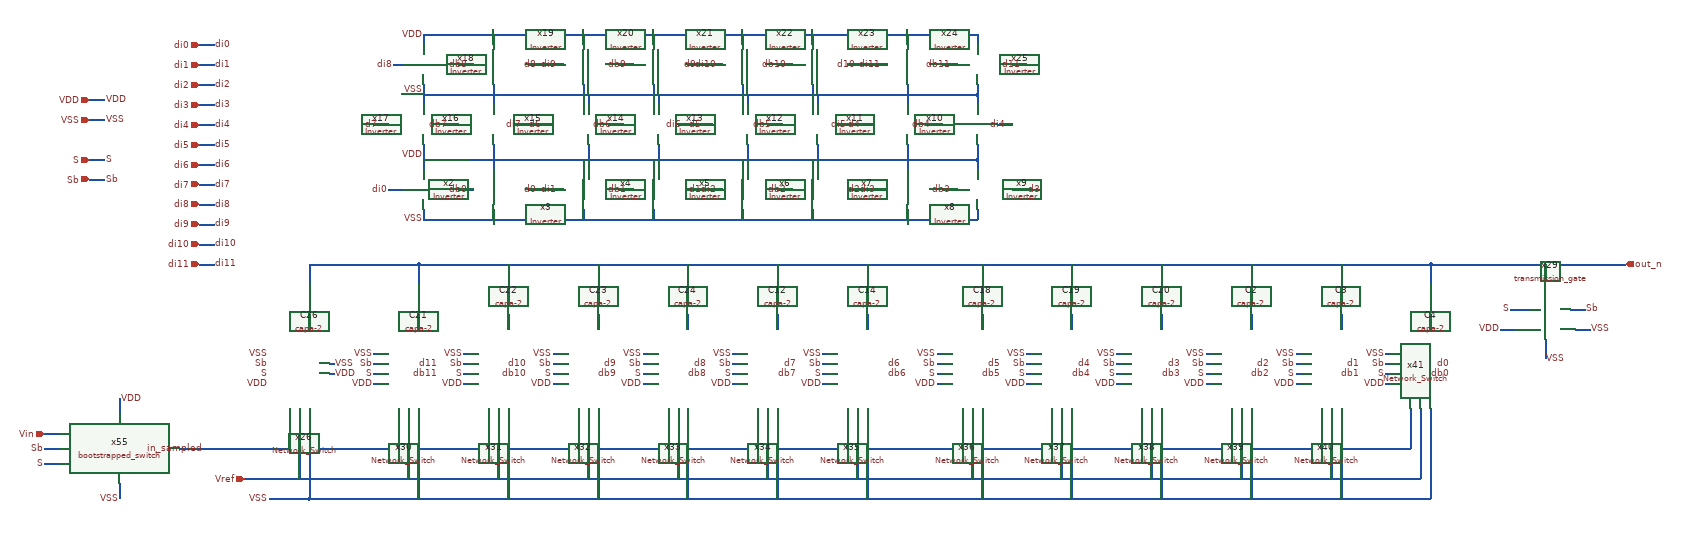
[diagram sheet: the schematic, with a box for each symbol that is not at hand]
v {xschem version=3.4.6 file_version=1.2}
G {}
K {}
V {}
S {}
E {}
N -780 60 -780 90 {lab=out_n}
N -520 60 200 60 {lab=out_n}
N 280 60 1000 60 {lab=out_n}
N 1250 60 1250 90 {lab=out_n}
N 1070 60 1070 90 {lab=out_n}
N 890 60 890 90 {lab=out_n}
N 710 60 710 90 {lab=out_n}
N 530 60 530 90 {lab=out_n}
N 350 60 350 90 {lab=out_n}
N 120 60 120 90 {lab=out_n}
N -60 60 -60 90 {lab=out_n}
N -240 60 -240 90 {lab=out_n}
N -420 60 -420 90 {lab=out_n}
N -600 60 -600 90 {lab=out_n}
N 1250 60 1640 60 {lab=out_n}
N -650 60 -520 60 {lab=out_n}
N -780 60 -650 60 {lab=out_n}
N -780 170 -780 190 {lab=#net1}
N -600 170 -600 190 {lab=#net2}
N -920 430 1210 430 {lab=in_p_sampled}
N 1210 350 1210 430 {lab=in_p_sampled}
N 1030 350 1030 430 {lab=in_p_sampled}
N 850 350 850 430 {lab=in_p_sampled}
N 670 350 670 430 {lab=in_p_sampled}
N 490 350 490 430 {lab=in_p_sampled}
N 310 350 310 430 {lab=in_p_sampled}
N -1440 -230 -1410 -230 {lab=VSS}
N -1440 -270 -1410 -270 {lab=VDD}
N -1440 -150 -1410 -150 {lab=S}
N -1440 -110 -1410 -110 {lab=Sb}
N -1220 -260 -1190 -260 {lab=di3}
N -1380 330 -1380 360 {lab=VDD}
N -870 300 -860 300 {lab=VDD}
N -690 300 -680 300 {lab=VDD}
N -510 300 -500 300 {lab=VDD}
N -330 300 -320 300 {lab=VDD}
N -150 300 -140 300 {lab=VDD}
N 30 300 40 300 {lab=VDD}
N 260 300 270 300 {lab=VDD}
N 440 300 450 300 {lab=VDD}
N 620 300 630 300 {lab=VDD}
N 980 300 990 300 {lab=VDD}
N 800 300 810 300 {lab=VDD}
N 1160 300 1170 300 {lab=VDD}
N -1380 500 -1380 530 {lab=VSS}
N -870 240 -860 240 {lab=VSS}
N -690 240 -680 240 {lab=VSS}
N -510 240 -500 240 {lab=VSS}
N -330 240 -320 240 {lab=VSS}
N -150 240 -140 240 {lab=VSS}
N 30 240 40 240 {lab=VSS}
N 260 240 270 240 {lab=VSS}
N 440 240 450 240 {lab=VSS}
N 620 240 630 240 {lab=VSS}
N 800 240 810 240 {lab=VSS}
N 980 240 990 240 {lab=VSS}
N 1160 240 1170 240 {lab=VSS}
N 1230 350 1230 490 {lab=Vref_p}
N -900 490 1230 490 {lab=Vref_p}
N 1250 350 1250 530 {lab=Vref_n}
N -920 530 1250 530 {lab=Vref_n}
N -800 350 -800 490 {lab=Vref_p}
N -780 350 -780 530 {lab=Vref_n}
N -620 350 -620 490 {lab=Vref_p}
N -600 350 -600 530 {lab=Vref_n}
N -440 350 -440 490 {lab=Vref_p}
N -420 350 -420 530 {lab=Vref_n}
N -260 350 -260 490 {lab=Vref_p}
N -240 350 -240 530 {lab=Vref_n}
N -80 350 -80 490 {lab=Vref_p}
N -60 350 -60 530 {lab=Vref_n}
N 100 350 100 490 {lab=Vref_p}
N 120 350 120 530 {lab=Vref_n}
N 330 350 330 490 {lab=Vref_p}
N 350 350 350 530 {lab=Vref_n}
N 510 350 510 490 {lab=Vref_p}
N 530 350 530 530 {lab=Vref_n}
N 690 350 690 490 {lab=Vref_p}
N 710 350 710 530 {lab=Vref_n}
N 870 350 870 490 {lab=Vref_p}
N 890 350 890 530 {lab=Vref_n}
N 1050 350 1050 490 {lab=Vref_p}
N 1070 350 1070 530 {lab=Vref_n}
N -1220 -380 -1190 -380 {lab=di0}
N -1220 -340 -1190 -340 {lab=di1}
N -1220 -300 -1190 -300 {lab=di2}
N -1220 -180 -1190 -180 {lab=di5}
N -1220 -220 -1190 -220 {lab=di4}
N -1220 -100 -1190 -100 {lab=di7}
N -1220 -140 -1190 -140 {lab=di6}
N -1220 -20 -1190 -20 {lab=di9}
N -1220 -60 -1190 -60 {lab=di8}
N -1220 60 -1190 60 {lab=di11}
N -1220 20 -1190 20 {lab=di10}
N -870 280 -860 280 {lab=S}
N -870 260 -860 260 {lab=Sb}
N -690 280 -680 280 {lab=S}
N -690 260 -680 260 {lab=Sb}
N -510 280 -500 280 {lab=S}
N -510 260 -500 260 {lab=Sb}
N -330 280 -320 280 {lab=S}
N -330 260 -320 260 {lab=Sb}
N -150 280 -140 280 {lab=S}
N -150 260 -140 260 {lab=Sb}
N 30 280 40 280 {lab=S}
N 30 260 40 260 {lab=Sb}
N 260 280 270 280 {lab=S}
N 260 260 270 260 {lab=Sb}
N 440 280 450 280 {lab=S}
N 440 260 450 260 {lab=Sb}
N 620 280 630 280 {lab=S}
N 620 260 630 260 {lab=Sb}
N 800 280 810 280 {lab=S}
N 800 260 810 260 {lab=Sb}
N 980 280 990 280 {lab=S}
N 980 260 990 260 {lab=Sb}
N 1160 280 1170 280 {lab=S}
N 1160 260 1170 260 {lab=Sb}
N -1530 400 -1500 400 {lab=Vin_p}
N -1530 460 -1500 460 {lab=S}
N -1530 430 -1500 430 {lab=Sb}
N 1250 90 1250 100 {lab=out_n}
N 1070 90 1070 100 {lab=out_n}
N 890 90 890 100 {lab=out_n}
N 710 90 710 100 {lab=out_n}
N 530 90 530 100 {lab=out_n}
N 350 90 350 100 {lab=out_n}
N 270 60 280 60 {lab=out_n}
N 200 60 210 60 {lab=out_n}
N -780 90 -780 100 {lab=out_n}
N -780 160 -780 170 {lab=#net1}
N -600 160 -600 170 {lab=#net2}
N -600 90 -600 100 {lab=out_n}
N -420 90 -420 100 {lab=out_n}
N -240 90 -240 100 {lab=out_n}
N 120 90 120 100 {lab=out_n}
N -60 90 -60 100 {lab=out_n}
N -1000 60 -1000 100 {lab=out_n}
N -1000 60 -780 60 {lab=out_n}
N -1000 530 -920 530 {lab=Vref_n}
N -1080 530 -1000 530 {lab=Vref_n}
N -770 -180 -770 -130 {lab=VDD}
N -770 -150 340 -150 {lab=VDD}
N 340 -150 340 -130 {lab=VDD}
N 340 -170 340 -150 {lab=VDD}
N 340 -180 340 -170 {lab=VDD}
N 200 -180 200 -150 {lab=VDD}
N 200 -150 200 -140 {lab=VDD}
N 200 -140 200 -130 {lab=VDD}
N 10 -150 10 -130 {lab=VDD}
N 20 -180 20 -150 {lab=VDD}
N -130 -150 -130 -130 {lab=VDD}
N -310 -150 -310 -130 {lab=VDD}
N -450 -150 -450 -130 {lab=VDD}
N -120 -180 -120 -150 {lab=VDD}
N -300 -180 -300 -150 {lab=VDD}
N -440 -180 -440 -150 {lab=VDD}
N -630 -180 -630 -150 {lab=VDD}
N -630 -150 -630 -130 {lab=VDD}
N -770 -300 -770 -260 {lab=VSS}
N -770 -280 340 -280 {lab=VSS}
N 340 -280 340 -260 {lab=VSS}
N 340 -300 340 -280 {lab=VSS}
N 200 -300 200 -280 {lab=VSS}
N 200 -280 200 -260 {lab=VSS}
N 20 -280 20 -260 {lab=VSS}
N 10 -300 10 -280 {lab=VSS}
N -120 -280 -120 -260 {lab=VSS}
N -130 -300 -130 -280 {lab=VSS}
N -310 -300 -310 -280 {lab=VSS}
N -300 -280 -300 -260 {lab=VSS}
N -440 -280 -440 -260 {lab=VSS}
N -450 -300 -450 -280 {lab=VSS}
N -630 -300 -630 -280 {lab=VSS}
N -630 -280 -630 -260 {lab=VSS}
N -770 -400 -770 -380 {lab=VDD}
N -770 -400 340 -400 {lab=VDD}
N 340 -400 340 -380 {lab=VDD}
N 200 -400 200 -380 {lab=VDD}
N 10 -400 10 -380 {lab=VDD}
N -130 -400 -130 -380 {lab=VDD}
N -630 -400 -630 -380 {lab=VDD}
N -450 -400 -450 -380 {lab=VDD}
N -310 -400 -310 -380 {lab=VDD}
N -700 -90 -670 -90 {lab=db0}
N -550 -90 -540 -90 {lab=d0}
N -560 -90 -550 -90 {lab=d0}
N -510 -90 -490 -90 {lab=di1}
N -370 -90 -350 -90 {lab=db1}
N -380 -90 -370 -90 {lab=db1}
N -840 -90 -810 -90 {lab=di0}
N -730 -220 -700 -220 {lab=db7}
N -590 -220 -560 -220 {lab=di7}
N -870 -220 -850 -220 {lab=d7}
N -540 -220 -520 -220 {lab=d6}
N -520 -220 -510 -220 {lab=d6}
N -400 -220 -370 -220 {lab=db6}
N -260 -220 -240 -220 {lab=di6}
N -210 -220 -190 -220 {lab=d5}
N -240 -90 -210 -90 {lab=d1}
N -190 -90 -170 -90 {lab=di2}
N -60 -90 -30 -90 {lab=db2}
N 80 -90 110 -90 {lab=d2}
N 140 -90 160 -90 {lab=di3}
N -80 -220 -60 -220 {lab=db5}
N 60 -220 80 -220 {lab=di5}
N 100 -220 120 -220 {lab=d4}
N 240 -220 270 -220 {lab=db4}
N 380 -220 410 -220 {lab=di4}
N 420 -90 450 -90 {lab=d3}
N 410 -90 420 -90 {lab=d3}
N 270 -90 300 -90 {lab=db3}
N 340 -50 340 -30 {lab=VSS}
N -770 -30 340 -30 {lab=VSS}
N -770 -50 -770 -30 {lab=VSS}
N -630 -50 -630 -30 {lab=VSS}
N -450 -50 -450 -30 {lab=VSS}
N -310 -50 -310 -30 {lab=VSS}
N 200 -50 200 -30 {lab=VSS}
N 10 -50 10 -30 {lab=VSS}
N -130 -50 -130 -30 {lab=VSS}
N 420 -340 440 -340 {lab=d11}
N 410 -340 420 -340 {lab=d11}
N 270 -340 300 -340 {lab=db11}
N 140 -340 160 -340 {lab=di11}
N -60 -340 -30 -340 {lab=db10}
N 80 -340 110 -340 {lab=d10}
N -190 -340 -170 -340 {lab=di10}
N -240 -340 -210 -340 {lab=d9}
N -700 -340 -670 -340 {lab=db8}
N -560 -340 -530 -340 {lab=d8}
N -510 -340 -490 -340 {lab=di9}
N -380 -340 -350 -340 {lab=db9}
N -830 -340 -810 -340 {lab=di8}
N -850 -220 -840 -220 {lab=d7}
N 120 -220 130 -220 {lab=d4}
N -60 -220 -50 -220 {lab=db5}
N -820 350 -820 380 {lab=in_p_sampled}
N -640 350 -640 380 {lab=in_p_sampled}
N -460 350 -460 380 {lab=in_p_sampled}
N -280 350 -280 380 {lab=in_p_sampled}
N -100 350 -100 380 {lab=in_p_sampled}
N 80 350 80 380 {lab=in_p_sampled}
N -820 380 -820 430 {lab=in_p_sampled}
N -640 380 -640 430 {lab=in_p_sampled}
N -460 380 -460 430 {lab=in_p_sampled}
N -280 380 -280 420 {lab=in_p_sampled}
N -280 420 -280 430 {lab=in_p_sampled}
N -100 380 -100 430 {lab=in_p_sampled}
N 80 380 80 430 {lab=in_p_sampled}
N 1480 60 1480 90 {lab=out_n}
N 1530 150 1560 150 {lab=Sb}
N 1410 150 1450 150 {lab=S}
N 1480 210 1480 230 {lab=Vcm}
N 1540 190 1570 190 {lab=VSS}
N 1390 190 1420 190 {lab=VDD}
N 1480 230 1480 250 {lab=Vcm}
N 210 60 270 60 {lab=out_n}
N -420 160 -420 190 {lab=#net3}
N -240 160 -240 190 {lab=#net4}
N -60 160 -60 190 {lab=#net5}
N 120 160 120 190 {lab=#net6}
N 350 160 350 190 {lab=#net7}
N 530 160 530 190 {lab=#net8}
N 710 160 710 190 {lab=#net9}
N 890 160 890 190 {lab=#net10}
N 1070 160 1070 190 {lab=#net11}
N 1250 160 1250 190 {lab=#net12}
N -960 280 -950 280 {lab=VDD}
N -960 260 -950 260 {lab=VSS}
N -1000 160 -1000 190 {lab=#net13}
N -1130 490 -900 490 {lab=Vref_p}
N -1000 350 -1000 530 {lab=Vref_n}
N -1020 350 -1020 490 {lab=Vref_p}
N -1260 430 -920 430 {lab=in_p_sampled}
N -1040 350 -1040 430 {lab=in_p_sampled}
N 1000 60 1250 60 {lab=out_n}
C {project/Network_Switch.sym} -800 270 2 1 {name=x30}
C {project/Network_Switch.sym} -620 270 2 1 {name=x31}
C {project/Network_Switch.sym} -440 270 2 1 {name=x32}
C {project/Network_Switch.sym} -260 270 2 1 {name=x33}
C {project/Network_Switch.sym} -80 270 2 1 {name=x34}
C {project/Network_Switch.sym} 100 270 2 1 {name=x35}
C {project/Network_Switch.sym} 330 270 2 1 {name=x36}
C {project/Network_Switch.sym} 510 270 2 1 {name=x37}
C {project/Network_Switch.sym} 690 270 2 1 {name=x38}
C {project/Network_Switch.sym} 870 270 2 1 {name=x39}
C {project/Network_Switch.sym} 1050 270 2 1 {name=x40}
C {project/Network_Switch.sym} 1230 270 2 1 {name=x41}
C {project/bootstrapped_switch.sym} -1380 430 0 0 {name=x55}
C {devices/ipin.sym} -1440 -270 0 0 {name=p5 lab=VDD}
C {devices/ipin.sym} -1440 -230 0 0 {name=p6 lab=VSS}
C {devices/ipin.sym} -1440 -150 0 0 {name=p7 lab=S}
C {devices/lab_pin.sym} -1410 -270 2 0 {name=p8 sig_type=std_logic lab=VDD}
C {devices/lab_pin.sym} -1410 -230 2 0 {name=p9 sig_type=std_logic lab=VSS}
C {devices/ipin.sym} -1440 -110 0 0 {name=p18 lab=Sb}
C {devices/ipin.sym} -1220 -260 0 0 {name=p19 lab=di3}
C {devices/lab_pin.sym} -1410 -150 2 0 {name=p21 sig_type=std_logic lab=S}
C {devices/lab_pin.sym} -1410 -110 2 0 {name=p22 sig_type=std_logic lab=Sb}
C {devices/lab_pin.sym} -1190 -260 2 0 {name=p27 sig_type=std_logic lab=di3}
C {devices/lab_pin.sym} -1380 330 2 0 {name=p4 sig_type=std_logic lab=VDD}
C {devices/lab_pin.sym} -870 300 0 0 {name=p29 sig_type=std_logic lab=VDD}
C {devices/lab_pin.sym} -690 300 0 0 {name=p30 sig_type=std_logic lab=VDD}
C {devices/lab_pin.sym} -510 300 0 0 {name=p31 sig_type=std_logic lab=VDD}
C {devices/lab_pin.sym} -330 300 0 0 {name=p32 sig_type=std_logic lab=VDD}
C {devices/lab_pin.sym} -150 300 0 0 {name=p33 sig_type=std_logic lab=VDD}
C {devices/lab_pin.sym} 30 300 0 0 {name=p34 sig_type=std_logic lab=VDD}
C {devices/lab_pin.sym} 260 300 0 0 {name=p35 sig_type=std_logic lab=VDD}
C {devices/lab_pin.sym} 440 300 0 0 {name=p36 sig_type=std_logic lab=VDD}
C {devices/lab_pin.sym} 620 300 0 0 {name=p37 sig_type=std_logic lab=VDD}
C {devices/lab_pin.sym} 980 300 0 0 {name=p38 sig_type=std_logic lab=VDD}
C {devices/lab_pin.sym} 800 300 0 0 {name=p39 sig_type=std_logic lab=VDD}
C {devices/lab_pin.sym} 1160 300 0 0 {name=p40 sig_type=std_logic lab=VDD}
C {devices/lab_pin.sym} -1380 530 0 0 {name=p45 sig_type=std_logic lab=VSS}
C {devices/lab_pin.sym} -870 240 0 0 {name=p46 sig_type=std_logic lab=VSS}
C {devices/lab_pin.sym} -690 240 0 0 {name=p47 sig_type=std_logic lab=VSS}
C {devices/lab_pin.sym} -510 240 0 0 {name=p48 sig_type=std_logic lab=VSS}
C {devices/lab_pin.sym} -330 240 0 0 {name=p49 sig_type=std_logic lab=VSS}
C {devices/lab_pin.sym} -150 240 0 0 {name=p50 sig_type=std_logic lab=VSS}
C {devices/lab_pin.sym} 30 240 0 0 {name=p51 sig_type=std_logic lab=VSS}
C {devices/lab_pin.sym} 260 240 0 0 {name=p52 sig_type=std_logic lab=VSS}
C {devices/lab_pin.sym} 440 240 0 0 {name=p53 sig_type=std_logic lab=VSS}
C {devices/lab_pin.sym} 620 240 0 0 {name=p54 sig_type=std_logic lab=VSS}
C {devices/lab_pin.sym} 800 240 0 0 {name=p55 sig_type=std_logic lab=VSS}
C {devices/lab_pin.sym} 980 240 0 0 {name=p56 sig_type=std_logic lab=VSS}
C {devices/lab_pin.sym} 1160 240 0 0 {name=p57 sig_type=std_logic lab=VSS}
C {devices/opin.sym} 1640 60 0 0 {name=p77 lab=out_n
}
C {devices/ipin.sym} -1220 -380 0 0 {name=p82 lab=di0}
C {devices/lab_pin.sym} -1190 -380 2 0 {name=p84 sig_type=std_logic lab=di0}
C {devices/ipin.sym} -1220 -340 0 0 {name=p86 lab=di1}
C {devices/lab_pin.sym} -1190 -340 2 0 {name=p88 sig_type=std_logic lab=di1}
C {devices/ipin.sym} -1220 -300 0 0 {name=p90 lab=di2}
C {devices/lab_pin.sym} -1190 -300 2 0 {name=p92 sig_type=std_logic lab=di2}
C {devices/ipin.sym} -1220 -180 0 0 {name=p94 lab=di5}
C {devices/lab_pin.sym} -1190 -180 2 0 {name=p96 sig_type=std_logic lab=di5}
C {devices/ipin.sym} -1220 -220 0 0 {name=p98 lab=di4}
C {devices/lab_pin.sym} -1190 -220 2 0 {name=p100 sig_type=std_logic lab=di4}
C {devices/ipin.sym} -1220 -100 0 0 {name=p102 lab=di7}
C {devices/lab_pin.sym} -1190 -100 2 0 {name=p104 sig_type=std_logic lab=di7}
C {devices/ipin.sym} -1220 -140 0 0 {name=p106 lab=di6}
C {devices/lab_pin.sym} -1190 -140 2 0 {name=p108 sig_type=std_logic lab=di6}
C {devices/ipin.sym} -1220 -20 0 0 {name=p110 lab=di9}
C {devices/lab_pin.sym} -1190 -20 2 0 {name=p112 sig_type=std_logic lab=di9}
C {devices/ipin.sym} -1220 -60 0 0 {name=p114 lab=di8}
C {devices/lab_pin.sym} -1190 -60 2 0 {name=p116 sig_type=std_logic lab=di8}
C {devices/ipin.sym} -1220 60 0 0 {name=p118 lab=di11}
C {devices/lab_pin.sym} -1190 60 2 0 {name=p120 sig_type=std_logic lab=di11}
C {devices/ipin.sym} -1220 20 0 0 {name=p122 lab=di10}
C {devices/lab_pin.sym} -1190 20 2 0 {name=p124 sig_type=std_logic lab=di10}
C {devices/lab_pin.sym} -870 280 2 1 {name=p152 sig_type=std_logic lab=S}
C {devices/lab_pin.sym} -870 260 2 1 {name=p153 sig_type=std_logic lab=Sb}
C {devices/lab_pin.sym} -690 280 2 1 {name=p150 sig_type=std_logic lab=S}
C {devices/lab_pin.sym} -690 260 2 1 {name=p151 sig_type=std_logic lab=Sb}
C {devices/lab_pin.sym} -510 280 2 1 {name=p154 sig_type=std_logic lab=S}
C {devices/lab_pin.sym} -510 260 2 1 {name=p155 sig_type=std_logic lab=Sb}
C {devices/lab_pin.sym} -330 280 2 1 {name=p156 sig_type=std_logic lab=S}
C {devices/lab_pin.sym} -330 260 2 1 {name=p157 sig_type=std_logic lab=Sb}
C {devices/lab_pin.sym} -150 280 2 1 {name=p158 sig_type=std_logic lab=S}
C {devices/lab_pin.sym} -150 260 2 1 {name=p159 sig_type=std_logic lab=Sb}
C {devices/lab_pin.sym} 30 280 2 1 {name=p160 sig_type=std_logic lab=S}
C {devices/lab_pin.sym} 30 260 2 1 {name=p161 sig_type=std_logic lab=Sb}
C {devices/lab_pin.sym} 260 280 2 1 {name=p162 sig_type=std_logic lab=S}
C {devices/lab_pin.sym} 260 260 2 1 {name=p163 sig_type=std_logic lab=Sb}
C {devices/lab_pin.sym} 440 280 2 1 {name=p164 sig_type=std_logic lab=S}
C {devices/lab_pin.sym} 440 260 2 1 {name=p165 sig_type=std_logic lab=Sb}
C {devices/lab_pin.sym} 620 280 2 1 {name=p166 sig_type=std_logic lab=S}
C {devices/lab_pin.sym} 620 260 2 1 {name=p167 sig_type=std_logic lab=Sb}
C {devices/lab_pin.sym} 800 280 2 1 {name=p168 sig_type=std_logic lab=S}
C {devices/lab_pin.sym} 800 260 2 1 {name=p169 sig_type=std_logic lab=Sb}
C {devices/lab_pin.sym} 980 280 2 1 {name=p170 sig_type=std_logic lab=S}
C {devices/lab_pin.sym} 980 260 2 1 {name=p171 sig_type=std_logic lab=Sb}
C {devices/lab_pin.sym} 1160 280 2 1 {name=p172 sig_type=std_logic lab=S}
C {devices/lab_pin.sym} 1160 260 2 1 {name=p173 sig_type=std_logic lab=Sb}
C {devices/lab_pin.sym} -740 280 0 0 {name=p180 sig_type=std_logic lab=db11}
C {devices/lab_pin.sym} -740 260 0 0 {name=p181 sig_type=std_logic lab=d11}
C {devices/lab_pin.sym} -560 280 0 0 {name=p182 sig_type=std_logic lab=db10}
C {devices/lab_pin.sym} -560 260 0 0 {name=p183 sig_type=std_logic lab=d10}
C {devices/lab_pin.sym} -380 280 0 0 {name=p184 sig_type=std_logic lab=db9}
C {devices/lab_pin.sym} -380 260 0 0 {name=p185 sig_type=std_logic lab=d9}
C {devices/lab_pin.sym} -200 260 0 0 {name=p187 sig_type=std_logic lab=d8}
C {devices/lab_pin.sym} -200 280 0 0 {name=p189 sig_type=std_logic lab=db8}
C {devices/lab_pin.sym} -20 260 0 0 {name=p191 sig_type=std_logic lab=d7}
C {devices/lab_pin.sym} -20 280 0 0 {name=p193 sig_type=std_logic lab=db7}
C {devices/lab_pin.sym} 160 260 2 0 {name=p195 sig_type=std_logic lab=d6}
C {devices/lab_pin.sym} 160 280 2 0 {name=p197 sig_type=std_logic lab=db6}
C {devices/lab_pin.sym} 390 260 0 0 {name=p199 sig_type=std_logic lab=d5}
C {devices/lab_pin.sym} 390 280 0 0 {name=p201 sig_type=std_logic lab=db5}
C {devices/lab_pin.sym} 570 280 0 0 {name=p204 sig_type=std_logic lab=db4}
C {devices/lab_pin.sym} 570 260 0 0 {name=p205 sig_type=std_logic lab=d4}
C {devices/lab_pin.sym} 750 260 0 0 {name=p206 sig_type=std_logic lab=d3}
C {devices/lab_pin.sym} 750 280 0 0 {name=p207 sig_type=std_logic lab=db3}
C {devices/lab_pin.sym} 930 280 0 0 {name=p212 sig_type=std_logic lab=db2}
C {devices/lab_pin.sym} 930 260 0 0 {name=p213 sig_type=std_logic lab=d2}
C {devices/lab_pin.sym} 1110 260 0 0 {name=p214 sig_type=std_logic lab=d1}
C {devices/lab_pin.sym} 1110 280 0 0 {name=p215 sig_type=std_logic lab=db1}
C {devices/lab_pin.sym} 1290 260 0 0 {name=p219 sig_type=std_logic lab=d0}
C {devices/lab_pin.sym} 1290 280 0 0 {name=p221 sig_type=std_logic lab=db0}
C {devices/ipin.sym} -1530 400 0 0 {name=p228 lab=Vin}
C {devices/lab_pin.sym} -1530 460 0 0 {name=p231 sig_type=std_logic lab=S}
C {devices/lab_pin.sym} -1530 430 0 0 {name=p232 sig_type=std_logic lab=Sb}
C {devices/lab_pin.sym} -1210 430 1 0 {name=p234 sig_type=std_logic lab=in_sampled}
C {devices/capa-2.sym} -1000 130 0 0 {name=C26
m=1
value=\{Cu\}
footprint=1206
device=polarized_capacitor}
C {project/Inverter.sym} -710 -90 0 0 {name=x2}
C {project/Inverter.sym} -570 -90 0 0 {name=x3}
C {project/Inverter.sym} -390 -90 0 0 {name=x4}
C {project/Inverter.sym} -250 -90 0 0 {name=x5}
C {project/Inverter.sym} -70 -90 0 0 {name=x6}
C {project/Inverter.sym} 70 -90 0 0 {name=x7}
C {project/Inverter.sym} 260 -90 0 0 {name=x8}
C {project/Inverter.sym} 400 -90 0 0 {name=x9}
C {project/Inverter.sym} 280 -220 2 0 {name=x10}
C {project/Inverter.sym} 140 -220 2 0 {name=x11}
C {project/Inverter.sym} -40 -220 2 0 {name=x12}
C {project/Inverter.sym} -180 -220 2 0 {name=x13}
C {project/Inverter.sym} -360 -220 2 0 {name=x14}
C {project/Inverter.sym} -500 -220 2 0 {name=x15}
C {project/Inverter.sym} -690 -220 2 0 {name=x16}
C {project/Inverter.sym} -830 -220 2 0 {name=x17}
C {project/Inverter.sym} -710 -340 0 0 {name=x18}
C {project/Inverter.sym} -570 -340 0 0 {name=x19}
C {project/Inverter.sym} -390 -340 0 0 {name=x20}
C {project/Inverter.sym} -250 -340 0 0 {name=x21}
C {project/Inverter.sym} -70 -340 0 0 {name=x22}
C {project/Inverter.sym} 70 -340 0 0 {name=x23}
C {project/Inverter.sym} 260 -340 0 0 {name=x24}
C {project/Inverter.sym} 400 -340 0 0 {name=x25}
C {devices/lab_pin.sym} -770 -160 0 0 {name=p238 sig_type=std_logic lab=VDD}
C {devices/lab_pin.sym} -770 -400 0 0 {name=p239 sig_type=std_logic lab=VDD}
C {devices/lab_pin.sym} -680 -90 1 0 {name=p240 sig_type=std_logic lab=db0}
C {devices/lab_pin.sym} -540 -90 1 0 {name=p241 sig_type=std_logic lab=d0}
C {devices/lab_pin.sym} -210 -90 1 0 {name=p242 sig_type=std_logic lab=d1}
C {devices/lab_pin.sym} -360 -90 1 0 {name=p243 sig_type=std_logic lab=db1}
C {devices/lab_pin.sym} 110 -90 1 0 {name=p244 sig_type=std_logic lab=d2}
C {devices/lab_pin.sym} -40 -90 1 0 {name=p245 sig_type=std_logic lab=db2}
C {devices/lab_pin.sym} 290 -90 1 0 {name=p246 sig_type=std_logic lab=db3}
C {devices/lab_pin.sym} 440 -90 2 0 {name=p247 sig_type=std_logic lab=d3}
C {devices/lab_pin.sym} 110 -220 3 0 {name=p248 sig_type=std_logic lab=d4}
C {devices/lab_pin.sym} 250 -220 3 0 {name=p249 sig_type=std_logic lab=db4}
C {devices/lab_pin.sym} -210 -220 3 0 {name=p250 sig_type=std_logic lab=d5}
C {devices/lab_pin.sym} -70 -220 3 0 {name=p251 sig_type=std_logic lab=db5}
C {devices/lab_pin.sym} -530 -220 3 0 {name=p252 sig_type=std_logic lab=d6}
C {devices/lab_pin.sym} -390 -220 3 0 {name=p253 sig_type=std_logic lab=db6}
C {devices/lab_pin.sym} -860 -220 3 0 {name=p254 sig_type=std_logic lab=d7}
C {devices/lab_pin.sym} -720 -220 3 0 {name=p255 sig_type=std_logic lab=db7}
C {devices/lab_pin.sym} -540 -340 3 0 {name=p256 sig_type=std_logic lab=d8}
C {devices/lab_pin.sym} -680 -340 3 0 {name=p257 sig_type=std_logic lab=db8}
C {devices/lab_pin.sym} -220 -340 3 0 {name=p258 sig_type=std_logic lab=d9}
C {devices/lab_pin.sym} -360 -340 3 0 {name=p259 sig_type=std_logic lab=db9}
C {devices/lab_pin.sym} -40 -340 3 0 {name=p260 sig_type=std_logic lab=db10}
C {devices/lab_pin.sym} 100 -340 3 0 {name=p261 sig_type=std_logic lab=d10}
C {devices/lab_pin.sym} 290 -340 3 0 {name=p262 sig_type=std_logic lab=db11}
C {devices/lab_pin.sym} 430 -340 3 0 {name=p263 sig_type=std_logic lab=d11}
C {devices/lab_pin.sym} -840 -90 0 0 {name=p264 sig_type=std_logic lab=di0}
C {devices/lab_pin.sym} -500 -90 1 0 {name=p265 sig_type=std_logic lab=di1}
C {devices/lab_pin.sym} -180 -90 1 0 {name=p266 sig_type=std_logic lab=di2}
C {devices/lab_pin.sym} 140 -90 1 0 {name=p267 sig_type=std_logic lab=di3}
C {devices/lab_pin.sym} 400 -220 1 0 {name=p268 sig_type=std_logic lab=di4}
C {devices/lab_pin.sym} 80 -220 1 0 {name=p269 sig_type=std_logic lab=di5}
C {devices/lab_pin.sym} -250 -220 1 0 {name=p270 sig_type=std_logic lab=di6}
C {devices/lab_pin.sym} -570 -220 1 0 {name=p271 sig_type=std_logic lab=di7}
C {devices/lab_pin.sym} -830 -340 1 0 {name=p272 sig_type=std_logic lab=di8}
C {devices/lab_pin.sym} -500 -340 1 0 {name=p273 sig_type=std_logic lab=di9}
C {devices/lab_pin.sym} -180 -340 1 0 {name=p274 sig_type=std_logic lab=di10}
C {devices/lab_pin.sym} 150 -340 1 0 {name=p275 sig_type=std_logic lab=di11}
C {devices/lab_pin.sym} -770 -30 0 0 {name=p276 sig_type=std_logic lab=VSS}
C {devices/lab_pin.sym} -770 -290 0 0 {name=p277 sig_type=std_logic lab=VSS}
C {project/transmission_gate.sym} 1480 140 3 0 {name=x29}
C {devices/lab_pin.sym} 1390 190 0 0 {name=p41 sig_type=std_logic lab=VDD}
C {devices/lab_pin.sym} 1570 190 2 0 {name=p73 sig_type=std_logic lab=VSS}
C {devices/lab_pin.sym} 1480 250 2 0 {name=p75 sig_type=std_logic lab=VSS}
C {devices/lab_pin.sym} 1410 150 0 0 {name=p223 sig_type=std_logic lab=S}
C {devices/lab_pin.sym} 1560 150 2 0 {name=p226 sig_type=std_logic lab=Sb}
C {devices/capa-2.sym} 890 130 0 1 {name=C2
m=1
value=\{4*Cu\}
footprint=1206
device=polarized_capacitor}
C {devices/capa-2.sym} 1070 130 0 1 {name=C3
m=1
value=\{2*Cu\}
footprint=1206
device=polarized_capacitor}
C {devices/capa-2.sym} 1250 130 0 1 {name=C4
m=1
value=\{Cu\}
footprint=1206
device=polarized_capacitor}
C {devices/capa-2.sym} -60 130 0 1 {name=C12
m=1
value=\{128*Cu\}
footprint=1206
device=polarized_capacitor}
C {devices/capa-2.sym} 120 130 0 1 {name=C14
m=1
value=\{64*Cu\}
footprint=1206
device=polarized_capacitor}
C {devices/capa-2.sym} 350 130 0 1 {name=C18
m=1
value=\{32*Cu\}
footprint=1206
device=polarized_capacitor}
C {devices/capa-2.sym} 530 130 0 1 {name=C19
m=1
value=\{16*Cu\}
footprint=1206
device=polarized_capacitor}
C {devices/capa-2.sym} 710 130 0 1 {name=C20
m=1
value=\{8*Cu\}
footprint=1206
device=polarized_capacitor}
C {devices/capa-2.sym} -780 130 0 1 {name=C21
m=1
value=\{2048*Cu\}
footprint=1206
device=polarized_capacitor}
C {devices/capa-2.sym} -600 130 0 1 {name=C22
m=1
value=\{1024*Cu\}
footprint=1206
device=polarized_capacitor}
C {devices/capa-2.sym} -420 130 0 1 {name=C23
m=1
value=\{512*Cu\}
footprint=1206
device=polarized_capacitor}
C {devices/capa-2.sym} -240 130 0 1 {name=C24
m=1
value=\{256*Cu\}
footprint=1206
device=polarized_capacitor}
C {project/Network_Switch.sym} -1020 270 2 1 {name=x26}
C {devices/lab_pin.sym} -1080 300 2 1 {name=p91 sig_type=std_logic lab=VDD}
C {devices/lab_pin.sym} -1080 240 2 1 {name=p93 sig_type=std_logic lab=VSS}
C {devices/lab_pin.sym} -1080 280 0 0 {name=p95 sig_type=std_logic lab=S}
C {devices/lab_pin.sym} -1080 260 0 0 {name=p97 sig_type=std_logic lab=Sb}
C {devices/lab_pin.sym} -950 280 0 1 {name=p99 sig_type=std_logic lab=VDD}
C {devices/lab_pin.sym} -950 260 0 1 {name=p101 sig_type=std_logic lab=VSS}
C {devices/ipin.sym} -1130 490 0 0 {name=p1 lab=Vref}
C {devices/lab_pin.sym} -1080 530 0 0 {name=p2 sig_type=std_logic lab=VSS}
